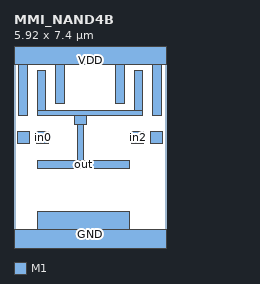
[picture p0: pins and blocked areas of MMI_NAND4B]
MACRO MMI_NAND4B
	CLASS CORE ;
	FOREIGN MMI_NAND4B 0 0 ;
	SIZE 5.92 BY 7.4 ;
	SYMMETRY X Y ;
	SITE CORE1 ;
	PIN out
		DIRECTION output ;
		USE SIGNAL ;
		PORT
			LAYER M1 ;
			RECT 0.9 5.14 1.24 6.67 ;
			LAYER M1 ;
			RECT 4.68 5.14 5.02 6.67 ;
			LAYER M1 ;
			RECT 0.9 4.91 5.02 5.14 ;
			LAYER M1 ;
			RECT 2.365 4.585 2.815 4.91 ;
			LAYER M1 ;
			RECT 2.485 3.19 2.715 4.585 ;
			LAYER M1 ;
			RECT 0.91 2.85 4.51 3.19 ;
		END
		AntennaDiffArea 3.7536 ;
	END out
	PIN in1
		DIRECTION input ;
		USE SIGNAL ;
		PORT
			LAYER M1 ;
			RECT 0.145 3.845 0.595 4.295 ;
		END
		AntennaGateArea 0.9936 ;
	END in1
	PIN GND
		DIRECTION inout ;
		USE GROUND ;
		PORT
			LAYER M1 ;
			RECT 0.91 0.5 4.51 1.18 ;
			LAYER M1 ;
			RECT 0 -0.5 5.92 0.5 ;
		END
	END GND
	PIN in2
		DIRECTION input ;
		USE SIGNAL ;
		PORT
			LAYER M1 ;
			RECT 4.585 3.845 5.035 4.295 ;
		END
		AntennaGateArea 0.9936 ;
	END in2
	PIN VDD
		DIRECTION inout ;
		USE POWER ;
		PORT
			LAYER M1 ;
			RECT 0 6.9 5.92 7.9 ;
			LAYER M1 ;
			RECT 0.18 4.91 0.52 6.9 ;
			LAYER M1 ;
			RECT 1.62 5.39 1.96 6.9 ;
			LAYER M1 ;
			RECT 3.96 5.39 4.3 6.9 ;
			LAYER M1 ;
			RECT 5.4 4.91 5.74 6.9 ;
		END
	END VDD
	PIN in3
		DIRECTION input ;
		USE SIGNAL ;
		PORT
			LAYER M1 ;
			RECT 5.325 3.845 5.775 4.295 ;
		END
		AntennaGateArea 0.9936 ;
	END in3
	PIN in0
		DIRECTION input ;
		USE SIGNAL ;
		PORT
			LAYER M1 ;
			RECT 0.885 3.845 1.335 4.295 ;
		END
		AntennaGateArea 0.9936 ;
	END in0
	OBS
	END
END MMI_NAND4B
